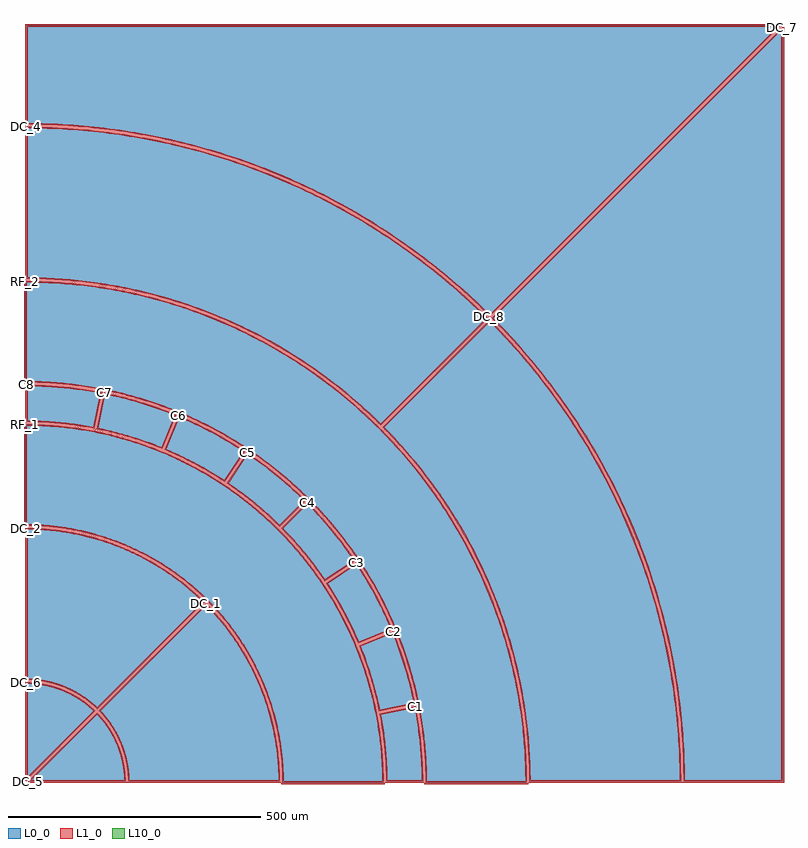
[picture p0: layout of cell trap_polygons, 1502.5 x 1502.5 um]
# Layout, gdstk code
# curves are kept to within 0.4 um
import gdstk
lib = gdstk.Library(unit=1e-6, precision=1e-09)
def P(c, l, *ps):  # polygons
    for p in ps: c.add(gdstk.Polygon(p, *l))
L0_0 = (0, 0)
L1_0 = (1, 0)
L10_0 = (10, 0)

trap_polygons = lib.new_cell('trap_polygons')
P(trap_polygons, L0_0, [(168.53,172.066),(123.841,214.523),(77.191,254.817),(28.686,292.857),(-21.566,328.558),(-73.452,361.839),(-108.893,382.645),(-135.896,397.51),(-190.918,425.3),(-247.195,450.454),(-304.6,472.915),(-363.004,492.633),(-422.275,509.563),(-452.195,516.971),(-492.346,525.742),(-532.753,533.24),(-563.203,538.025),(-624.399,545.425),(-685.878,549.919),(-747.5,551.498),(-747.5,747.5),(743.964,747.5)],
  [(747.5,743.964),(747.5,-747.5),(551.498,-747.5),(549.919,-685.878),(545.425,-624.399),(538.025,-563.203),(533.24,-532.753),(525.742,-492.346),(516.971,-452.195),(509.563,-422.275),(492.633,-363.004),(472.915,-304.6),(450.454,-247.195),(425.3,-190.918),(397.51,-135.896),(382.645,-108.893),(361.839,-73.452),(328.558,-21.566),(292.857,28.686),(254.817,77.191),(214.523,123.841),(172.066,168.53)],
  [(-747.5,-551.516),(-727.732,-552.753),(-709.676,-555.639),(-690.507,-560.625),(-673.334,-566.903),(-656.811,-574.734),(-639.808,-584.894),(-625.083,-595.734),(-611.418,-607.883),(-747.5,-743.964)],
  [(-743.964,-747.5),(-607.883,-611.418),(-595.734,-625.083),(-584.894,-639.808),(-574.734,-656.811),(-566.903,-673.334),(-560.625,-690.507),(-555.639,-709.676),(-552.753,-727.732),(-551.516,-747.5)],
  [(-747.5,546.498),(-686.116,544.925),(-645.264,542.263),(-614.691,539.42),(-553.791,531.567),(-493.331,520.84),(-433.447,507.261),(-374.272,490.863),(-315.941,471.681),(-258.583,449.759),(-202.327,425.145),(-147.3,397.896),(-93.625,368.072),(-67.332,352.215),(-32.873,330.112),(-7.496,312.827),(25.689,288.854),(74.007,250.962),(120.477,210.823),(164.994,168.53),(-47.138,-43.603),(-81.321,-11.162),(-123.086,24.591),(-160.408,53.364),(-199.049,80.341),(-238.922,105.46),(-279.938,128.666),(-329.113,153.253),(-372.287,172.142),(-416.307,188.968),(-461.073,203.695),(-514.109,218.178),(-560.147,228.247),(-606.609,236.129),(-653.391,241.806),(-700.39,245.264),(-747.5,246.497)],
  [(168.53,164.994),(210.823,120.477),(250.962,74.007),(288.854,25.689),(312.827,-7.496),(330.112,-32.873),(352.215,-67.332),(368.072,-93.625),(397.896,-147.3),(425.145,-202.327),(449.759,-258.583),(471.681,-315.941),(490.863,-374.272),(507.261,-433.447),(520.84,-493.331),(531.567,-553.791),(539.42,-614.691),(542.263,-645.264),(544.925,-686.116),(546.498,-747.5),(246.497,-747.5),(245.264,-700.39),(241.806,-653.391),(236.129,-606.609),(228.247,-560.147),(218.178,-514.109),(203.695,-461.073),(188.968,-416.307),(172.142,-372.287),(153.253,-329.113),(128.666,-279.938),(105.46,-238.922),(80.341,-199.049),(53.364,-160.408),(24.591,-123.086),(-11.162,-81.321),(-43.603,-47.138)],
  [(-747.5,-246.506),(-723.848,-247.18),(-700.254,-248.963),(-676.77,-251.854),(-653.448,-255.844),(-626.511,-261.878),(-603.715,-268.219),(-581.242,-275.623),(-559.142,-284.076),(-533.895,-295.235),(-512.768,-305.89),(-492.166,-317.526),(-472.132,-330.117),(-449.539,-345.976),(-430.889,-360.538),(-412.944,-375.96),(-395.744,-392.208),(-607.882,-604.347),(-621.9,-591.878),(-637.006,-580.753),(-654.45,-570.327),(-671.402,-562.291),(-690.516,-555.388),(-708.691,-550.737),(-727.217,-547.779),(-747.5,-546.515)],
  [(-392.208,-395.744),(-375.96,-412.944),(-360.538,-430.889),(-345.976,-449.539),(-330.117,-472.132),(-317.526,-492.166),(-305.89,-512.768),(-295.235,-533.895),(-284.076,-559.142),(-275.623,-581.242),(-268.219,-603.715),(-261.878,-626.511),(-255.844,-653.448),(-251.854,-676.77),(-248.963,-700.254),(-247.18,-723.848),(-246.506,-747.5),(-546.515,-747.5),(-547.779,-727.217),(-550.737,-708.691),(-555.388,-690.516),(-562.291,-671.402),(-570.327,-654.45),(-580.753,-637.006),(-591.878,-621.9),(-604.347,-607.882)],
  [(-747.5,36.496),(-710.16,35.49),(-672.91,32.713),(-635.833,28.17),(-599.014,21.871),(-613.256,-49.726),(-646.544,-44.04),(-680.065,-39.936),(-713.742,-37.422),(-747.5,-36.504)],
  [(-594.11,20.896),(-557.684,12.625),(-521.691,2.634),(-486.213,-9.055),(-451.331,-22.416),(-479.267,-89.859),(-510.806,-77.788),(-542.882,-67.223),(-575.421,-58.187),(-608.352,-50.702)],
  [(-446.711,-24.329),(-412.598,-39.548),(-379.246,-56.369),(-346.731,-74.755),(-315.125,-94.664),(-355.682,-155.361),(-384.26,-137.369),(-413.658,-120.749),(-443.81,-105.539),(-474.647,-91.773)],
  [(-310.968,-97.441),(-280.479,-119.023),(-251.05,-142.027),(-222.746,-166.403),(-195.631,-192.096),(-247.25,-243.715),(-271.77,-220.493),(-297.36,-198.457),(-323.965,-177.657),(-351.524,-158.139)],
  [(-192.096,-195.631),(-166.403,-222.746),(-142.027,-251.05),(-119.023,-280.479),(-97.441,-310.968),(-158.139,-351.524),(-177.657,-323.965),(-198.457,-297.36),(-220.493,-271.77),(-243.715,-247.25)],
  [(-94.664,-315.125),(-74.755,-346.731),(-56.369,-379.246),(-39.548,-412.598),(-24.329,-446.711),(-91.773,-474.647),(-105.539,-443.81),(-120.749,-413.658),(-137.369,-384.26),(-155.361,-355.682)],
  [(-22.416,-451.331),(-9.055,-486.213),(2.634,-521.691),(12.625,-557.684),(20.896,-594.11),(-50.702,-608.352),(-58.187,-575.421),(-67.223,-542.882),(-77.788,-510.806),(-89.859,-479.267)],
  [(21.871,-599.014),(28.17,-635.833),(32.713,-672.91),(35.49,-710.16),(36.496,-747.5),(-36.504,-747.5),(-37.422,-713.742),(-39.936,-680.065),(-44.04,-646.544),(-49.726,-613.256)],
  [(-750,241.5),(-703.294,240.399),(-656.692,237.1),(-602.591,230.481),(-556.568,222.449),(-510.974,212.257),(-458.459,197.669),(-414.141,182.883),(-370.569,166.027),(-320.807,143.793),(-279.18,122.583),(-238.598,99.435),(-199.152,74.402),(-154.683,42.887),(-117.994,13.964),(-82.708,-16.656),(-48.904,-48.904),(-16.656,-82.708),(13.964,-117.994),(42.887,-154.683),(74.402,-199.152),(99.435,-238.598),(122.583,-279.18),(143.793,-320.807),(166.027,-370.569),(182.883,-414.141),(197.669,-458.459),(212.257,-510.974),(222.449,-556.568),(230.481,-602.591),(237.1,-656.692),(240.399,-703.294),(241.5,-750),(41.5,-750),(40.89,-718.926),(38.548,-681.704),(35.259,-650.799),(30.759,-620.046),(25.055,-589.494),(16.634,-553.162),(8.315,-523.216),(-3.21,-487.746),(-14.082,-458.629),(-28.624,-424.286),(-41.968,-396.216),(-59.419,-363.256),(-75.135,-336.442),(-91.892,-310.266),(-109.663,-284.768),(-132.289,-255.12),(-160.416,-221.925),(-190.325,-190.325),(-221.925,-160.416),(-255.12,-132.289),(-289.811,-106.029),(-325.893,-81.714),(-363.256,-59.419),(-407.381,-36.498),(-447.106,-18.749),(-487.746,-3.21),(-529.179,10.072),(-571.278,21.058),(-613.918,29.714),(-656.969,36.014),(-706.507,40.304),(-750,41.5)],
  [(-750,-41.5),(-716.625,-42.287),(-683.324,-44.644),(-650.171,-48.568),(-611.779,-55.114),(-579.198,-62.396),(-546.997,-71.205),(-510.004,-83.386),(-478.869,-95.431),(-448.335,-108.93),(-413.564,-126.475),(-384.566,-143.016),(-356.378,-160.904),(-324.602,-183.423),(-298.385,-204.091),(-273.171,-225.971),(-249.015,-249.015),(-225.971,-273.171),(-204.091,-298.385),(-183.423,-324.602),(-160.904,-356.378),(-143.016,-384.566),(-126.475,-413.564),(-108.93,-448.335),(-95.431,-478.869),(-83.386,-510.004),(-71.205,-546.997),(-62.396,-579.198),(-55.114,-611.779),(-48.568,-650.171),(-44.644,-683.324),(-42.287,-716.625),(-41.5,-750),(-241.5,-750),(-242.064,-726.046),(-244.148,-698.171),(-247.151,-674.4),(-251.271,-650.797),(-256.497,-627.413),(-263.979,-600.48),(-271.562,-577.752),(-280.207,-555.405),(-289.895,-533.491),(-300.605,-512.058),(-314.359,-487.723),(-327.198,-467.493),(-340.975,-447.889),(-355.66,-428.957),(-371.221,-410.738),(-390.436,-390.436),(-410.738,-371.221),(-428.957,-355.66),(-447.889,-340.975),(-467.493,-327.198),(-487.723,-314.359),(-512.058,-300.605),(-533.491,-289.895),(-555.405,-280.207),(-577.752,-271.562),(-600.48,-263.979),(-627.413,-256.497),(-650.797,-251.271),(-674.4,-247.151),(-698.171,-244.148),(-726.046,-242.064),(-750,-241.5)])
P(trap_polygons, L1_0, [(-238.718,449.579),(-274.853,464.352),(-303.744,475.264),(-362.26,495.02),(-421.646,511.982),(-481.768,526.114),(-542.492,537.384),(-573.037,541.937),(-613.916,546.88),(-675.475,551.869),(-706.326,553.268),(-745,553.983),(-745,745),(-238.718,745),(-238.718,750),(-750,750),(-750,549.012),(-686.001,547.422),(-624.641,542.937),(-563.561,535.551),(-502.901,525.281),(-462.76,516.844),(-432.84,509.687),(-403.098,501.823),(-363.747,490.246),(-305.455,470.566),(-267.14,455.922),(-238.718,444.149)],
  [(168.53,172.066),(170.298,170.298),(747.5,747.5),(746.464,750),(-238.718,750),(-238.718,745),(737.929,745),(168.52,175.591),(125.519,216.376),(78.78,256.747),(30.181,294.86),(-20.167,330.629),(-72.153,363.974),(-125.659,394.821),(-180.566,423.099),(-238.718,449.579),(-238.718,444.149),(-182.749,418.601),(-155.234,404.84),(-119.069,385.486),(-66.012,354.338),(-14.49,320.713),(27.19,290.854),(67.659,259.373),(114.535,219.526),(144.715,191.746),(166.773,170.287)],
  [(750,-246.229),(745,-246.229),(745,-745),(553.983,-745),(553.268,-706.326),(551.869,-675.475),(546.88,-613.916),(541.937,-573.037),(537.384,-542.492),(526.114,-481.768),(517.009,-441.612),(506.641,-401.762),(495.02,-362.26),(485.488,-332.885),(468.066,-284.455),(452.76,-246.229),(447.33,-246.229),(470.566,-305.455),(490.246,-363.747),(507.144,-422.905),(516.844,-462.76),(523.291,-492.841),(529.024,-523.066),(535.551,-563.561),(542.937,-624.641),(547.422,-686.001),(549.012,-750),(750,-750)],
  [(750,743.964),(747.501,743.964),(745.732,745.732),(168.54,168.54),(212.67,122.162),(252.887,75.602),(290.854,27.19),(326.486,-22.965),(359.703,-74.752),(390.431,-128.053),(418.601,-182.749),(431.706,-210.582),(447.33,-246.229),(452.76,-246.229),(436.255,-208.506),(413.962,-162.115),(394.821,-125.659),(379.714,-98.723),(358.589,-63.38),(342.018,-37.319),(318.972,-3.197),(300.987,21.909),(263.259,70.806),(223.257,117.863),(202.432,140.667),(175.591,168.52),(745,737.929),(745,-246.229),(750,-246.229)],
  [(-607.883,-607.883),(-617.607,-598.761),(-628.367,-589.98),(-639.707,-581.963),(-650.232,-575.508),(-666.931,-566.969),(-679.887,-566.969),(-661.996,-574.868),(-644.98,-584.51),(-629.01,-595.801),(-614.989,-607.918),(-745,-737.929),(-745,-566.969),(-750,-566.969),(-750,-746.464),(-747.5,-747.5)],
  [(-668.118,-566.434),(-691.232,-557.783),(-713.713,-552.303),(-730.521,-549.946),(-745.925,-549.041),(-747.459,-549.016),(-747.5,-551.516),(-750,-551.516),(-750,-566.969),(-745,-566.969),(-745,-554.065),(-728.012,-555.237),(-711.659,-557.787),(-695.579,-561.707),(-679.887,-566.969),(-666.931,-566.969)],
  [(-567.068,-745),(-737.929,-745),(-607.918,-614.989),(-595.801,-629.01),(-584.51,-644.98),(-574.868,-661.996),(-567.068,-679.632),(-567.068,-666.711),(-575.508,-650.232),(-581.963,-639.707),(-589.98,-628.367),(-598.761,-617.607),(-607.883,-607.883),(-745.732,-745.732),(-743.964,-747.501),(-743.964,-750),(-567.068,-750)],
  [(-548.975,-749.959),(-550.102,-728.986),(-553.51,-707.658),(-559.188,-686.82),(-567.068,-666.711),(-567.068,-679.632),(-561.707,-695.579),(-557.787,-711.659),(-555.237,-728.012),(-554.065,-745),(-567.068,-745),(-567.068,-750)],
  [(-461.798,206.52),(-498.246,216.758),(-528.848,224.214),(-559.67,230.702),(-598.461,237.44),(-637.486,242.644),(-668.836,245.697),(-708.132,248.122),(-745,248.981),(-745,543.983),(-686.239,542.428),(-625.116,537.96),(-584.514,533.375),(-544.078,527.51),(-503.847,520.372),(-461.798,511.491),(-461.798,516.622),(-492.836,523.29),(-533.165,530.775),(-573.71,536.982),(-604.236,540.796),(-634.844,543.886),(-675.752,546.876),(-706.484,548.271),(-747.485,548.998),(-747.5,546.498),(-750,546.498),(-750,244.013),(-716.171,243.424),(-684.87,241.864),(-653.634,239.318),(-622.493,235.788),(-583.749,229.998),(-537.603,221.042),(-499.506,211.919),(-461.798,201.302)],
  [(-184.934,419.651),(-219.929,435.928),(-257.635,452.072),(-286.239,463.395),(-324.78,477.432),(-363.745,490.245),(-393.223,499.044),(-422.902,507.143),(-461.798,516.622),(-461.798,511.491),(-414.285,499.692),(-374.997,488.47),(-336.082,476.013),(-297.581,462.334),(-240.686,439.553),(-184.934,414.103)],
  [(-184.934,73.831),(-217.505,95.251),(-251.224,115.577),(-285.717,134.558),(-320.932,152.165),(-356.813,168.371),(-393.305,183.15),(-430.351,196.481),(-461.798,206.52),(-461.798,201.302),(-424.537,189.207),(-387.783,175.654),(-351.59,160.662),(-323.08,147.65),(-288.041,130.131),(-253.72,111.245),(-220.17,91.021),(-184.934,67.754)],
  [(168.53,168.53),(129.728,205.761),(91.327,239.732),(43.521,278.458),(2.319,308.97),(-40.056,337.833),(-92.359,370.228),(-137.077,395.307),(-184.934,419.651),(-184.934,414.103),(-130.449,386.043),(-86.102,360.709),(-42.789,333.646),(7.727,298.945),(48.53,268.227),(88.089,235.922),(126.342,202.082),(161.449,168.52),(-47.149,-40.078),(-79.644,-9.309),(-115.412,21.556),(-152.599,50.695),(-184.934,73.831),(-184.934,67.754),(-149.328,41.978),(-112.556,12.693),(-77.21,-18.297),(-47.127,-47.127)],
  [(549.012,-749.985),(548.574,-716.734),(546.876,-675.752),(543.886,-634.844),(540.796,-604.236),(536.982,-573.71),(530.775,-533.165),(523.29,-492.836),(516.287,-460.348),(511.156,-460.348),(520.372,-503.847),(527.51,-544.078),(533.375,-584.514),(537.96,-625.116),(542.428,-686.239),(543.983,-745),(248.981,-745),(247.761,-700.266),(245.027,-660.99),(240.747,-621.852),(234.928,-582.913),(225.927,-536.534),(212.669,-483.036),(206.087,-460.348),(200.857,-460.348),(209.915,-491.931),(219.338,-529.955),(227.256,-568.321),(233.655,-606.968),(237.676,-638.05),(241.32,-677.054),(243.424,-716.171),(244.013,-750)],
  [(203.774,-452.821),(188.658,-408.06),(174.455,-371.34),(158.817,-335.208),(141.767,-299.72),(119.482,-258.062),(91.028,-210.859),(73.613,-184.613),(67.532,-184.613),(86.818,-213.557),(103.314,-240.205),(122.739,-274.224),(137.304,-301.973),(157.494,-344.424),(172.77,-380.497),(186.612,-417.144),(200.857,-460.348),(206.087,-460.348)],
  [(514.536,-452.764),(504.521,-412.988),(493.256,-373.548),(480.75,-334.483),(467.018,-295.833),(448.148,-248.161),(423.043,-191.993),(419.496,-184.613),(413.946,-184.613),(427.158,-212.659),(443.536,-250.093),(455.04,-278.497),(469.325,-316.778),(482.395,-355.49),(491.392,-384.785),(502.304,-424.161),(511.156,-460.348),(516.287,-460.348)],
  [(418.601,-182.75),(395.307,-137.077),(370.228,-92.359),(337.833,-40.056),(308.97,2.319),(278.458,43.521),(246.343,83.488),(212.676,122.156),(170.308,166.752),(168.53,164.995),(166.762,166.762),(-47.127,-47.127),(-18.297,-77.21),(12.693,-112.556),(41.978,-149.328),(67.532,-184.613),(73.613,-184.613),(45.962,-146.306),(21.556,-115.412),(-9.309,-79.644),(-40.078,-47.149),(168.52,161.449),(202.082,126.342),(235.922,88.089),(268.227,48.53),(298.945,7.727),(333.646,-42.789),(360.709,-86.102),(386.043,-130.449),(413.946,-184.613),(419.496,-184.613)],
  [(-553.504,-553.504),(-560.575,-553.504),(-607.911,-600.84),(-607.274,-601.456),(-619.1,-590.937),(-632.998,-580.452),(-647.731,-571.178),(-661.762,-563.855),(-674.838,-558.201),(-688.151,-553.504),(-707.687,-553.504),(-694.208,-556.898),(-680.996,-561.216),(-668.114,-566.436),(-654.263,-573.265),(-642.277,-580.304),(-629.567,-589.075),(-618.733,-597.783),(-607.854,-607.854)],
  [(-688.273,-553.465),(-702.004,-549.669),(-715.963,-546.831),(-731.662,-544.818),(-745.886,-544.041),(-745,-544.055),(-745,-311.848),(-750,-311.848),(-750,-548.975),(-729.032,-550.097),(-707.687,-553.504)],
  [(-392.208,-392.208),(-408.337,-376.768),(-426.249,-361.128),(-441.723,-348.75),(-460.915,-334.71),(-477.397,-323.709),(-496.907,-311.848),(-507.052,-311.848),(-476.793,-330.049),(-451.031,-347.982),(-423.456,-370.04),(-399.295,-392.224),(-560.575,-553.504),(-553.504,-553.504)],
  [(-497.726,-311.373),(-529.249,-294.693),(-561.868,-280.274),(-595.422,-268.189),(-625.898,-259.455),(-660.76,-251.932),(-696.065,-246.883),(-719.761,-244.904),(-747.478,-244.006),(-747.5,-246.506),(-750,-246.506),(-750,-311.848),(-745,-311.848),(-745,-249.028),(-716.144,-250.145),(-684.908,-253.247),(-657.782,-257.56),(-627.124,-264.302),(-596.95,-272.95),(-567.376,-283.471),(-538.519,-295.823),(-507.052,-311.848),(-496.907,-311.848)],
  [(-553.504,-688.151),(-561.87,-666.077),(-572.771,-644.995),(-586.026,-625.307),(-601.456,-607.274),(-600.84,-607.911),(-553.504,-560.575),(-553.504,-553.504),(-607.854,-607.854),(-597.783,-618.733),(-589.075,-629.567),(-580.304,-642.277),(-573.265,-654.263),(-566.436,-668.114),(-561.216,-680.996),(-556.898,-694.208),(-553.504,-707.687)],
  [(-392.224,-399.295),(-370.04,-423.456),(-350.336,-447.891),(-330.049,-476.793),(-313.362,-504.346),(-313.362,-494.298),(-325.858,-474.066),(-341.617,-451.237),(-358.604,-429.305),(-376.768,-408.337),(-390.425,-393.992),(-392.209,-395.744),(-393.976,-393.976),(-553.504,-553.504),(-553.504,-560.575)],
  [(-313.362,-745),(-544.055,-745),(-544.041,-745.886),(-544.818,-731.662),(-546.831,-715.963),(-549.669,-702.004),(-553.504,-688.151),(-553.504,-707.687),(-550.097,-729.032),(-548.975,-750),(-313.362,-750)],
  [(-243.984,-749.978),(-245.157,-715.806),(-248.289,-684.258),(-254.166,-649.081),(-261.459,-618.229),(-271.954,-584.144),(-283.279,-554.533),(-296.436,-525.689),(-313.362,-494.298),(-313.362,-504.346),(-297.494,-534.968),(-284.916,-563.727),(-272.95,-596.95),(-264.302,-627.124),(-257.56,-657.782),(-253.247,-684.908),(-250.145,-716.144),(-249.029,-745),(-313.362,-745),(-313.362,-750)],
  [(-747.482,38.996),(-747.518,33.996),(-710.286,32.993),(-673.155,30.225),(-636.196,25.696),(-601.957,19.89),(-615.224,-46.805),(-646.182,-41.567),(-679.82,-37.448),(-713.615,-34.925),(-745,-34.023),(-745,36.496),(-750,36.496),(-750,-38.986),(-713.869,-39.919),(-680.31,-42.424),(-646.907,-46.514),(-611.288,-52.648),(-596.089,23.857),(-635.47,30.643),(-672.664,35.201),(-710.033,37.987)],
  [(-593.605,23.344),(-594.615,18.448),(-558.295,10.201),(-522.417,0.241),(-487.052,-11.411),(-454.604,-23.785),(-480.627,-86.61),(-509.968,-75.433),(-542.156,-64.831),(-574.81,-55.763),(-605.416,-48.756),(-591.658,20.408),(-596.562,21.384),(-611.288,-52.648),(-576.033,-60.612),(-543.608,-69.615),(-511.644,-80.144),(-477.907,-93.109),(-448.074,-21.039),(-485.375,-6.7),(-520.965,5.026),(-557.072,15.049)],
  [(-445.738,-22.026),(-447.684,-26.632),(-413.671,-41.806),(-380.425,-58.574),(-348.013,-76.901),(-318.602,-95.368),(-356.382,-151.909),(-382.979,-135.222),(-412.48,-118.544),(-442.737,-103.281),(-471.388,-90.437),(-444.402,-25.286),(-449.021,-23.372),(-477.907,-93.109),(-444.883,-107.797),(-414.837,-122.954),(-385.542,-139.516),(-354.982,-158.813),(-311.662,-93.949),(-345.449,-72.608),(-378.068,-54.164),(-411.526,-37.289)],
  [(-309.564,-95.373),(-312.371,-99.51),(-281.972,-121.028),(-252.636,-143.96),(-224.422,-168.258),(-199.179,-192.108),(-247.263,-240.192),(-270.094,-218.637),(-295.774,-196.525),(-322.472,-175.652),(-348.067,-157.465),(-308.889,-98.83),(-313.046,-96.052),(-354.982,-158.813),(-325.458,-179.662),(-298.946,-200.39),(-273.445,-222.348),(-247.237,-247.237),(-192.096,-192.07),(-221.07,-164.548),(-249.464,-140.095),(-278.987,-117.017)],
  [(-190.315,-193.876),(-193.876,-197.386),(-168.258,-224.422),(-143.96,-252.636),(-121.028,-281.972),(-100.924,-310.288),(-157.465,-348.067),(-175.652,-322.472),(-196.525,-295.774),(-218.637,-270.094),(-240.192,-247.263),(-190.328,-197.399),(-193.863,-193.863),(-247.237,-247.237),(-222.348,-273.445),(-200.39,-298.946),(-179.662,-325.458),(-158.813,-354.982),(-93.969,-311.633),(-117.017,-278.987),(-140.095,-249.464),(-164.548,-221.07)],
  [(-92.575,-313.751),(-96.752,-316.499),(-76.901,-348.013),(-58.574,-380.425),(-41.806,-413.671),(-27.612,-445.365),(-90.437,-471.388),(-103.281,-442.737),(-118.544,-412.48),(-135.222,-382.979),(-151.909,-356.382),(-93.275,-317.204),(-96.052,-313.046),(-158.813,-354.982),(-139.516,-385.542),(-122.954,-414.837),(-107.797,-444.883),(-93.109,-477.907),(-21.053,-448.041),(-37.289,-411.526),(-54.164,-378.068),(-72.608,-345.449)],
  [(-20.099,-450.39),(-24.732,-452.271),(-11.411,-487.052),(0.241,-522.417),(10.201,-558.295),(17.939,-592.15),(-48.756,-605.416),(-55.763,-574.81),(-64.831,-542.156),(-75.433,-509.968),(-86.61,-480.627),(-21.459,-453.64),(-23.372,-449.021),(-93.109,-477.907),(-80.144,-511.644),(-69.615,-543.608),(-60.612,-576.033),(-52.648,-611.288),(23.85,-596.053),(15.049,-557.072),(5.026,-520.965),(-6.7,-485.375)],
  [(24.327,-598.544),(19.416,-599.484),(25.696,-636.196),(30.225,-673.155),(32.993,-710.286),(33.978,-745),(-34.023,-745),(-34.925,-713.615),(-37.448,-679.82),(-41.567,-646.182),(-46.805,-615.224),(22.359,-601.466),(21.384,-596.562),(-52.648,-611.288),(-46.514,-646.907),(-42.424,-680.31),(-39.919,-713.869),(-38.986,-750),(39.014,-749.982),(37.987,-710.033),(35.201,-672.664),(30.643,-635.47)],
  [(-481.545,-2.762),(-516.532,8.9),(-546.506,17.48),(-576.794,24.878),(-613.488,32.177),(-650.485,37.739),(-681.489,41.039),(-712.597,43.119),(-747.5,43.99),(-747.5,238.99),(-718.935,238.512),(-687.9,237.048),(-633.756,232.145),(-595.286,226.824),(-557.056,219.997),(-519.123,211.674),(-481.545,201.868),(-481.545,207.058),(-517.955,216.536),(-556.08,224.901),(-586.798,230.511),(-625.419,236.162),(-664.231,240.293),(-710.976,243.234),(-749.99,244),(-750,241.5),(-752.5,241.5),(-752.5,39.01),(-725.217,38.611),(-694.275,37.03),(-663.42,34.235),(-632.697,30.231),(-596.074,23.84),(-553.784,14.212),(-518.002,4.121),(-481.545,-8.079)],
  [(-234.338,99.772),(-264.31,117.261),(-291.791,132.089),(-326.775,149.398),(-355.235,162.248),(-384.084,174.198),(-420.65,187.851),(-450.271,197.733),(-481.545,207.058),(-481.545,201.868),(-444.382,190.595),(-407.69,177.871),(-371.526,163.717),(-335.946,148.154),(-287.217,124.044),(-259.991,109.077),(-234.338,93.923)],
  [(-234.338,-146.238),(-263.352,-122.617),(-293.446,-100.389),(-319.301,-82.966),(-351.201,-63.418),(-383.986,-45.394),(-417.584,-28.934),(-451.92,-14.076),(-481.545,-2.762),(-481.545,-8.079),(-448.063,-21.059),(-414.06,-36.091),(-380.803,-52.709),(-353.713,-67.741),(-322.014,-87.166),(-291.265,-108.063),(-261.535,-130.385),(-234.338,-152.836)],
  [(-45.394,-48.892),(-63.89,-30.772),(-86.82,-9.575),(-110.405,10.89),(-134.621,30.605),(-159.444,49.549),(-184.85,67.705),(-210.813,85.053),(-234.338,99.772),(-234.338,93.923),(-207.016,76.613),(-174.982,54.659),(-149.991,36.2),(-119.588,12.038),(-84.391,-18.505),(-45.394,-55.99)],
  [(-45.394,-383.986),(-63.418,-351.201),(-82.966,-319.301),(-103.995,-288.358),(-126.458,-258.439),(-150.306,-229.612),(-179.808,-197.445),(-206.47,-171.199),(-234.338,-146.238),(-234.338,-152.836),(-209.892,-174.844),(-183.398,-200.925),(-158.162,-228.225),(-134.24,-256.684),(-108.063,-291.265),(-87.166,-322.014),(-64.65,-359.083),(-45.394,-394.976)],
  [(54.659,-166.429),(30.605,-134.621),(5.844,-104.449),(-20.083,-75.272),(-45.394,-48.892),(-45.394,-55.99),(-18.505,-84.391),(7.063,-113.622),(31.463,-143.835),(54.659,-174.982)],
  [(54.659,-747.5),(43.99,-747.5),(43.388,-718.828),(42.017,-693.922),(36.933,-644.302),(28.744,-595.098),(22.062,-564.644),(15.859,-540.485),(3.189,-498.717),(-11.757,-457.709),(-28.934,-417.584),(-45.394,-383.986),(-45.394,-394.976),(-33.475,-419.677),(-23.453,-442.347),(-14.148,-465.32),(-3.539,-494.429),(7.672,-529.876),(18.623,-571.843),(28.293,-620.457),(34.235,-663.42),(37.808,-706.644),(39.01,-752.5),(54.659,-752.5)],
  [(244.01,-752.49),(243.234,-710.976),(240.936,-672.012),(237.11,-633.168),(231.762,-594.504),(224.901,-556.08),(216.536,-517.955),(206.681,-480.188),(195.35,-442.837),(182.562,-405.96),(168.336,-369.613),(152.694,-333.852),(135.661,-298.733),(117.261,-264.31),(97.524,-230.636),(76.481,-197.763),(54.659,-166.429),(54.659,-174.982),(80.853,-213.525),(101.274,-246.558),(120.383,-280.367),(141.539,-321.889),(154.546,-350.104),(169.549,-385.925),(183.134,-422.307),(192.966,-451.779),(201.868,-481.545),(211.674,-519.123),(219.997,-557.056),(226.824,-595.286),(232.145,-633.756),(235.951,-672.404),(238.237,-711.172),(238.99,-747.5),(54.659,-747.5),(54.659,-752.5)],
  [(-569.374,-271.988),(-588.28,-265.265),(-611.294,-258.185),(-634.616,-252.197),(-658.193,-247.315),(-681.975,-243.548),(-701.911,-241.268),(-725.929,-239.567),(-747.5,-239.01),(-747.5,-44.01),(-700.137,-45.763),(-656.016,-50.284),(-612.266,-57.566),(-569.374,-67.498),(-569.374,-62.33),(-594.9,-56.123),(-616.772,-51.594),(-660.888,-44.606),(-705.356,-40.403),(-749.99,-39),(-750,-41.5),(-752.5,-41.5),(-752.5,-243.99),(-714.263,-245.264),(-674.772,-249.623),(-647.39,-254.513),(-620.318,-260.9),(-593.637,-268.765),(-569.374,-277.341)],
  [(-405.033,-128.3),(-442.228,-109.065),(-483.08,-91.005),(-524.985,-75.545),(-569.374,-62.33),(-569.374,-67.498),(-526.567,-80.288),(-484.957,-95.639),(-444.392,-113.573),(-405.033,-134.018)],
  [(-405.033,-373.018),(-424.276,-356.268),(-443.185,-341.361),(-462.775,-327.362),(-483.003,-314.301),(-503.824,-302.207),(-525.191,-291.108),(-547.057,-281.027),(-569.374,-271.988),(-569.374,-277.341),(-545.402,-287.209),(-520.281,-299.151),(-495.854,-312.455),(-472.194,-327.081),(-452.581,-340.637),(-436.738,-352.63),(-421.379,-365.235),(-405.033,-379.825)],
  [(-282.636,-214.197),(-309.824,-191.64),(-341.171,-168.296),(-373.754,-146.709),(-405.033,-128.3),(-405.033,-134.018),(-371.706,-153.905),(-339.522,-175.592),(-308.579,-199.016),(-282.636,-220.847)],
  [(-282.636,-543.38),(-292.888,-521.594),(-306.129,-496.821),(-318.548,-476.192),(-334.246,-452.898),(-351.2,-430.501),(-366.693,-412.07),(-385.842,-391.517),(-405.033,-373.018),(-405.033,-379.825),(-383.874,-400.733),(-365.235,-421.379),(-347.758,-443.019),(-329.276,-468.881),(-316.501,-489.012),(-304.688,-509.723),(-293.864,-530.966),(-282.636,-556.078)],
  [(-174.789,-332.085),(-198.623,-301.108),(-224.122,-271.488),(-251.211,-243.314),(-282.636,-214.197),(-282.636,-220.847),(-250.783,-250.783),(-224.105,-278.969),(-199.016,-308.579),(-174.789,-340.655)],
  [(-174.789,-747.5),(-239.01,-747.5),(-239.772,-721.92),(-242.086,-693.926),(-245.291,-670.062),(-250.446,-642.449),(-256.067,-619.036),(-264.01,-592.092),(-273.421,-565.626),(-282.636,-543.38),(-282.636,-556.078),(-273.914,-578.599),(-265.215,-605.019),(-257.981,-631.877),(-252.233,-659.092),(-248.504,-682.641),(-245.887,-706.339),(-244.39,-730.135),(-243.99,-752.5),(-174.789,-752.5)],
  [(-38.99,-752.49),(-39.548,-722.086),(-41.192,-694.216),(-43.928,-666.431),(-47.754,-638.775),(-52.662,-611.291),(-58.645,-584.02),(-65.694,-557.006),(-73.799,-530.289),(-82.946,-503.911),(-93.122,-477.912),(-104.31,-452.333),(-116.494,-427.213),(-129.655,-402.59),(-143.773,-378.504),(-158.825,-354.99),(-174.789,-332.085),(-174.789,-340.655),(-156.894,-367.036),(-142.316,-390.617),(-128.675,-414.751),(-113.573,-444.392),(-104.287,-464.533),(-93.578,-490.104),(-83.88,-516.075),(-76.861,-537.114),(-69.022,-563.706),(-63.507,-585.188),(-57.566,-612.266),(-52.692,-639.557),(-48.894,-667.019),(-46.176,-694.608),(-44.544,-722.283),(-44.01,-747.5),(-174.789,-747.5),(-174.789,-752.5)])
P(trap_polygons, L10_0, [(0,0),(0,0),(0,0),(0,0)])
trap_polygons.add(gdstk.Label('DC_8', (168.53,172.066), layer=2, texttype=0))
trap_polygons.add(gdstk.Label('DC_7', (747.5,743.964), layer=2, texttype=0))
trap_polygons.add(gdstk.Label('DC_6', (-747.5,-551.516), layer=2, texttype=0))
trap_polygons.add(gdstk.Label('DC_5', (-743.964,-747.5), layer=2, texttype=0))
trap_polygons.add(gdstk.Label('DC_4', (-747.5,546.498), layer=2, texttype=0))
trap_polygons.add(gdstk.Label('DC_3', (168.53,164.994), layer=2, texttype=0))
trap_polygons.add(gdstk.Label('DC_2', (-747.5,-246.506), layer=2, texttype=0))
trap_polygons.add(gdstk.Label('DC_1', (-392.208,-395.744), layer=2, texttype=0))
trap_polygons.add(gdstk.Label('C8', (-747.5,36.496), layer=2, texttype=0))
trap_polygons.add(gdstk.Label('C7', (-594.11,20.896), layer=2, texttype=0))
trap_polygons.add(gdstk.Label('C6', (-446.711,-24.329), layer=2, texttype=0))
trap_polygons.add(gdstk.Label('C5', (-310.968,-97.441), layer=2, texttype=0))
trap_polygons.add(gdstk.Label('C4', (-192.096,-195.631), layer=2, texttype=0))
trap_polygons.add(gdstk.Label('C3', (-94.664,-315.125), layer=2, texttype=0))
trap_polygons.add(gdstk.Label('C2', (-22.416,-451.331), layer=2, texttype=0))
trap_polygons.add(gdstk.Label('C1', (21.871,-599.014), layer=2, texttype=0))
trap_polygons.add(gdstk.Label('RF_2', (-750,241.5), layer=2, texttype=0))
trap_polygons.add(gdstk.Label('RF_1', (-750,-41.5), layer=2, texttype=0))

lib.write_gds('trap_polygons.gds')
